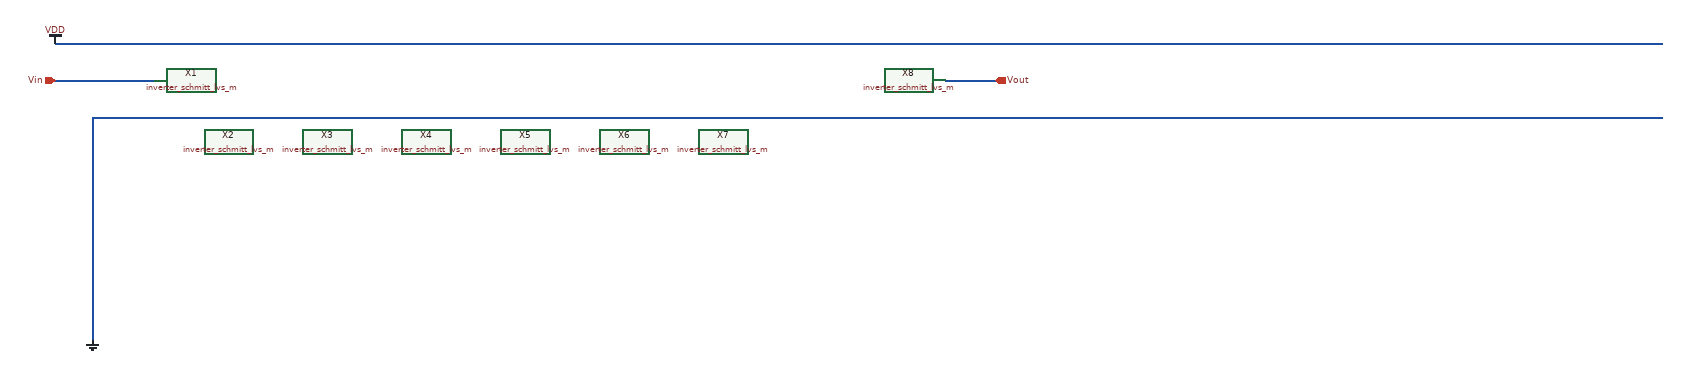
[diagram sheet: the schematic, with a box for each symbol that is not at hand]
v {xschem version=2.9.9 file_version=1.2 }
G {}
K {}
V {}
S {}
E {}
N 80 -540 2680 -540 { lab=VDD}
N 140 -420 280 -420 { lab=GND}
N 280 -420 2680 -420 { lab=GND}
N 140 -420 140 -60 { lab=GND}
N 1520 -480 1600 -480 { lab=Vout}
N 80 -480 240 -480 { lab=Vin}
C {devices/ipin.sym} 80 -480 0 0 {name=p1 lab=Vin}
C {devices/opin.sym} 1600 -480 0 0 {name=p4 lab=Vout}
C {madvlsi/vdd.sym} 80 -540 0 0 {name=l1 lab=VDD}
C {madvlsi/gnd.sym} 140 -60 0 0 {name=l2 lab=GND}
C {/home/madvlsi/Desktop/MADVLSI_final/schematics/inverter_schmitt_lvs_m.sym} 200 -380 0 0 {name=X1}
C {/home/madvlsi/Desktop/MADVLSI_final/schematics/inverter_schmitt_lvs_m.sym} 360 -380 0 0 {name=X2}
C {/home/madvlsi/Desktop/MADVLSI_final/schematics/inverter_schmitt_lvs_m.sym} 520 -380 0 0 {name=X3}
C {/home/madvlsi/Desktop/MADVLSI_final/schematics/inverter_schmitt_lvs_m.sym} 680 -380 0 0 {name=X4}
C {/home/madvlsi/Desktop/MADVLSI_final/schematics/inverter_schmitt_lvs_m.sym} 840 -380 0 0 {name=X5}
C {/home/madvlsi/Desktop/MADVLSI_final/schematics/inverter_schmitt_lvs_m.sym} 1000 -380 0 0 {name=X6}
C {/home/madvlsi/Desktop/MADVLSI_final/schematics/inverter_schmitt_lvs_m.sym} 1160 -380 0 0 {name=X7}
C {/home/madvlsi/Desktop/MADVLSI_final/schematics/inverter_schmitt_lvs_m.sym} 1320 -380 0 0 {name=X8}
